VERSION 5.7 ;
  NOWIREEXTENSIONATPIN ON ;
  DIVIDERCHAR "/" ;
  BUSBITCHARS "[]" ;
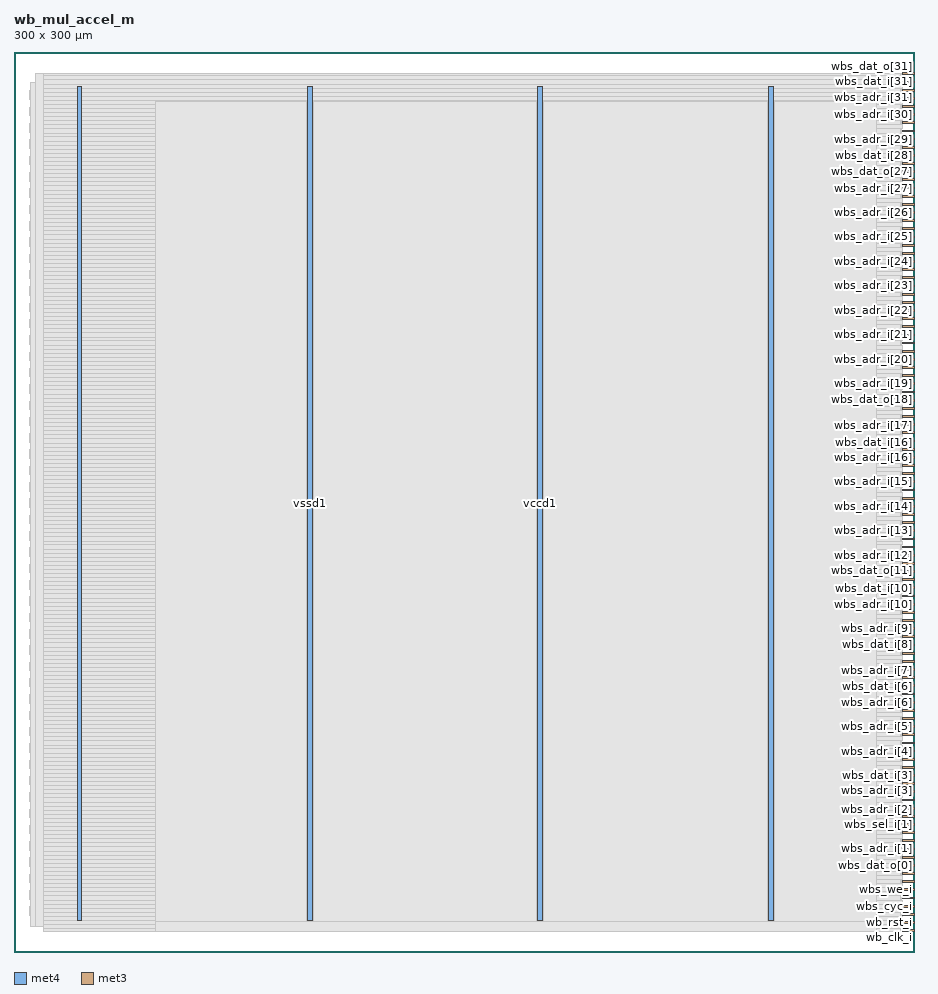
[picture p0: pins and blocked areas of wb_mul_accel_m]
MACRO wb_mul_accel_m
  CLASS BLOCK ;
  FOREIGN wb_mul_accel_m ;
  ORIGIN 0.000 0.000 ;
  SIZE 300.000 BY 300.000 ;
  PIN vccd1
    DIRECTION INOUT ;
    USE POWER ;
    PORT
      LAYER met4 ;
        RECT 21.040 10.640 22.640 288.560 ;
    END
    PORT
      LAYER met4 ;
        RECT 174.640 10.640 176.240 288.560 ;
    END
  END vccd1
  PIN vssd1
    DIRECTION INOUT ;
    USE GROUND ;
    PORT
      LAYER met4 ;
        RECT 97.840 10.640 99.440 288.560 ;
    END
    PORT
      LAYER met4 ;
        RECT 251.440 10.640 253.040 288.560 ;
    END
  END vssd1
  PIN wb_clk_i
    DIRECTION INPUT ;
    USE SIGNAL ;
    ANTENNAGATEAREA 0.852000 ;
    PORT
      LAYER met3 ;
        RECT 296.000 6.840 300.000 7.440 ;
    END
  END wb_clk_i
  PIN wb_rst_i
    DIRECTION INPUT ;
    USE SIGNAL ;
    ANTENNAGATEAREA 0.213000 ;
    PORT
      LAYER met3 ;
        RECT 296.000 9.560 300.000 10.160 ;
    END
  END wb_rst_i
  PIN wbs_ack_o
    DIRECTION OUTPUT TRISTATE ;
    USE SIGNAL ;
    ANTENNADIFFAREA 0.795200 ;
    PORT
      LAYER met3 ;
        RECT 296.000 12.280 300.000 12.880 ;
    END
  END wbs_ack_o
  PIN wbs_adr_i[0]
    DIRECTION INPUT ;
    USE SIGNAL ;
    PORT
      LAYER met3 ;
        RECT 296.000 23.160 300.000 23.760 ;
    END
  END wbs_adr_i[0]
  PIN wbs_adr_i[10]
    DIRECTION INPUT ;
    USE SIGNAL ;
    PORT
      LAYER met3 ;
        RECT 296.000 115.640 300.000 116.240 ;
    END
  END wbs_adr_i[10]
  PIN wbs_adr_i[11]
    DIRECTION INPUT ;
    USE SIGNAL ;
    PORT
      LAYER met3 ;
        RECT 296.000 123.800 300.000 124.400 ;
    END
  END wbs_adr_i[11]
  PIN wbs_adr_i[12]
    DIRECTION INPUT ;
    USE SIGNAL ;
    PORT
      LAYER met3 ;
        RECT 296.000 131.960 300.000 132.560 ;
    END
  END wbs_adr_i[12]
  PIN wbs_adr_i[13]
    DIRECTION INPUT ;
    USE SIGNAL ;
    PORT
      LAYER met3 ;
        RECT 296.000 140.120 300.000 140.720 ;
    END
  END wbs_adr_i[13]
  PIN wbs_adr_i[14]
    DIRECTION INPUT ;
    USE SIGNAL ;
    PORT
      LAYER met3 ;
        RECT 296.000 148.280 300.000 148.880 ;
    END
  END wbs_adr_i[14]
  PIN wbs_adr_i[15]
    DIRECTION INPUT ;
    USE SIGNAL ;
    PORT
      LAYER met3 ;
        RECT 296.000 156.440 300.000 157.040 ;
    END
  END wbs_adr_i[15]
  PIN wbs_adr_i[16]
    DIRECTION INPUT ;
    USE SIGNAL ;
    PORT
      LAYER met3 ;
        RECT 296.000 164.600 300.000 165.200 ;
    END
  END wbs_adr_i[16]
  PIN wbs_adr_i[17]
    DIRECTION INPUT ;
    USE SIGNAL ;
    PORT
      LAYER met3 ;
        RECT 296.000 172.760 300.000 173.360 ;
    END
  END wbs_adr_i[17]
  PIN wbs_adr_i[18]
    DIRECTION INPUT ;
    USE SIGNAL ;
    PORT
      LAYER met3 ;
        RECT 296.000 180.920 300.000 181.520 ;
    END
  END wbs_adr_i[18]
  PIN wbs_adr_i[19]
    DIRECTION INPUT ;
    USE SIGNAL ;
    PORT
      LAYER met3 ;
        RECT 296.000 189.080 300.000 189.680 ;
    END
  END wbs_adr_i[19]
  PIN wbs_adr_i[1]
    DIRECTION INPUT ;
    USE SIGNAL ;
    PORT
      LAYER met3 ;
        RECT 296.000 34.040 300.000 34.640 ;
    END
  END wbs_adr_i[1]
  PIN wbs_adr_i[20]
    DIRECTION INPUT ;
    USE SIGNAL ;
    PORT
      LAYER met3 ;
        RECT 296.000 197.240 300.000 197.840 ;
    END
  END wbs_adr_i[20]
  PIN wbs_adr_i[21]
    DIRECTION INPUT ;
    USE SIGNAL ;
    PORT
      LAYER met3 ;
        RECT 296.000 205.400 300.000 206.000 ;
    END
  END wbs_adr_i[21]
  PIN wbs_adr_i[22]
    DIRECTION INPUT ;
    USE SIGNAL ;
    PORT
      LAYER met3 ;
        RECT 296.000 213.560 300.000 214.160 ;
    END
  END wbs_adr_i[22]
  PIN wbs_adr_i[23]
    DIRECTION INPUT ;
    USE SIGNAL ;
    PORT
      LAYER met3 ;
        RECT 296.000 221.720 300.000 222.320 ;
    END
  END wbs_adr_i[23]
  PIN wbs_adr_i[24]
    DIRECTION INPUT ;
    USE SIGNAL ;
    PORT
      LAYER met3 ;
        RECT 296.000 229.880 300.000 230.480 ;
    END
  END wbs_adr_i[24]
  PIN wbs_adr_i[25]
    DIRECTION INPUT ;
    USE SIGNAL ;
    PORT
      LAYER met3 ;
        RECT 296.000 238.040 300.000 238.640 ;
    END
  END wbs_adr_i[25]
  PIN wbs_adr_i[26]
    DIRECTION INPUT ;
    USE SIGNAL ;
    PORT
      LAYER met3 ;
        RECT 296.000 246.200 300.000 246.800 ;
    END
  END wbs_adr_i[26]
  PIN wbs_adr_i[27]
    DIRECTION INPUT ;
    USE SIGNAL ;
    PORT
      LAYER met3 ;
        RECT 296.000 254.360 300.000 254.960 ;
    END
  END wbs_adr_i[27]
  PIN wbs_adr_i[28]
    DIRECTION INPUT ;
    USE SIGNAL ;
    PORT
      LAYER met3 ;
        RECT 296.000 262.520 300.000 263.120 ;
    END
  END wbs_adr_i[28]
  PIN wbs_adr_i[29]
    DIRECTION INPUT ;
    USE SIGNAL ;
    PORT
      LAYER met3 ;
        RECT 296.000 270.680 300.000 271.280 ;
    END
  END wbs_adr_i[29]
  PIN wbs_adr_i[2]
    DIRECTION INPUT ;
    USE SIGNAL ;
    ANTENNAGATEAREA 0.213000 ;
    PORT
      LAYER met3 ;
        RECT 296.000 44.920 300.000 45.520 ;
    END
  END wbs_adr_i[2]
  PIN wbs_adr_i[30]
    DIRECTION INPUT ;
    USE SIGNAL ;
    PORT
      LAYER met3 ;
        RECT 296.000 278.840 300.000 279.440 ;
    END
  END wbs_adr_i[30]
  PIN wbs_adr_i[31]
    DIRECTION INPUT ;
    USE SIGNAL ;
    PORT
      LAYER met3 ;
        RECT 296.000 287.000 300.000 287.600 ;
    END
  END wbs_adr_i[31]
  PIN wbs_adr_i[3]
    DIRECTION INPUT ;
    USE SIGNAL ;
    ANTENNAGATEAREA 0.196500 ;
    PORT
      LAYER met3 ;
        RECT 296.000 55.800 300.000 56.400 ;
    END
  END wbs_adr_i[3]
  PIN wbs_adr_i[4]
    DIRECTION INPUT ;
    USE SIGNAL ;
    PORT
      LAYER met3 ;
        RECT 296.000 66.680 300.000 67.280 ;
    END
  END wbs_adr_i[4]
  PIN wbs_adr_i[5]
    DIRECTION INPUT ;
    USE SIGNAL ;
    PORT
      LAYER met3 ;
        RECT 296.000 74.840 300.000 75.440 ;
    END
  END wbs_adr_i[5]
  PIN wbs_adr_i[6]
    DIRECTION INPUT ;
    USE SIGNAL ;
    PORT
      LAYER met3 ;
        RECT 296.000 83.000 300.000 83.600 ;
    END
  END wbs_adr_i[6]
  PIN wbs_adr_i[7]
    DIRECTION INPUT ;
    USE SIGNAL ;
    PORT
      LAYER met3 ;
        RECT 296.000 91.160 300.000 91.760 ;
    END
  END wbs_adr_i[7]
  PIN wbs_adr_i[8]
    DIRECTION INPUT ;
    USE SIGNAL ;
    PORT
      LAYER met3 ;
        RECT 296.000 99.320 300.000 99.920 ;
    END
  END wbs_adr_i[8]
  PIN wbs_adr_i[9]
    DIRECTION INPUT ;
    USE SIGNAL ;
    PORT
      LAYER met3 ;
        RECT 296.000 107.480 300.000 108.080 ;
    END
  END wbs_adr_i[9]
  PIN wbs_cyc_i
    DIRECTION INPUT ;
    USE SIGNAL ;
    ANTENNAGATEAREA 0.196500 ;
    PORT
      LAYER met3 ;
        RECT 296.000 15.000 300.000 15.600 ;
    END
  END wbs_cyc_i
  PIN wbs_dat_i[0]
    DIRECTION INPUT ;
    USE SIGNAL ;
    ANTENNAGATEAREA 0.196500 ;
    PORT
      LAYER met3 ;
        RECT 296.000 25.880 300.000 26.480 ;
    END
  END wbs_dat_i[0]
  PIN wbs_dat_i[10]
    DIRECTION INPUT ;
    USE SIGNAL ;
    ANTENNAGATEAREA 0.196500 ;
    PORT
      LAYER met3 ;
        RECT 296.000 118.360 300.000 118.960 ;
    END
  END wbs_dat_i[10]
  PIN wbs_dat_i[11]
    DIRECTION INPUT ;
    USE SIGNAL ;
    ANTENNAGATEAREA 0.196500 ;
    PORT
      LAYER met3 ;
        RECT 296.000 126.520 300.000 127.120 ;
    END
  END wbs_dat_i[11]
  PIN wbs_dat_i[12]
    DIRECTION INPUT ;
    USE SIGNAL ;
    ANTENNAGATEAREA 0.196500 ;
    PORT
      LAYER met3 ;
        RECT 296.000 134.680 300.000 135.280 ;
    END
  END wbs_dat_i[12]
  PIN wbs_dat_i[13]
    DIRECTION INPUT ;
    USE SIGNAL ;
    ANTENNAGATEAREA 0.196500 ;
    PORT
      LAYER met3 ;
        RECT 296.000 142.840 300.000 143.440 ;
    END
  END wbs_dat_i[13]
  PIN wbs_dat_i[14]
    DIRECTION INPUT ;
    USE SIGNAL ;
    ANTENNAGATEAREA 0.196500 ;
    PORT
      LAYER met3 ;
        RECT 296.000 151.000 300.000 151.600 ;
    END
  END wbs_dat_i[14]
  PIN wbs_dat_i[15]
    DIRECTION INPUT ;
    USE SIGNAL ;
    ANTENNAGATEAREA 0.196500 ;
    PORT
      LAYER met3 ;
        RECT 296.000 159.160 300.000 159.760 ;
    END
  END wbs_dat_i[15]
  PIN wbs_dat_i[16]
    DIRECTION INPUT ;
    USE SIGNAL ;
    ANTENNAGATEAREA 0.196500 ;
    PORT
      LAYER met3 ;
        RECT 296.000 167.320 300.000 167.920 ;
    END
  END wbs_dat_i[16]
  PIN wbs_dat_i[17]
    DIRECTION INPUT ;
    USE SIGNAL ;
    ANTENNAGATEAREA 0.196500 ;
    PORT
      LAYER met3 ;
        RECT 296.000 175.480 300.000 176.080 ;
    END
  END wbs_dat_i[17]
  PIN wbs_dat_i[18]
    DIRECTION INPUT ;
    USE SIGNAL ;
    ANTENNAGATEAREA 0.196500 ;
    PORT
      LAYER met3 ;
        RECT 296.000 183.640 300.000 184.240 ;
    END
  END wbs_dat_i[18]
  PIN wbs_dat_i[19]
    DIRECTION INPUT ;
    USE SIGNAL ;
    ANTENNAGATEAREA 0.196500 ;
    PORT
      LAYER met3 ;
        RECT 296.000 191.800 300.000 192.400 ;
    END
  END wbs_dat_i[19]
  PIN wbs_dat_i[1]
    DIRECTION INPUT ;
    USE SIGNAL ;
    ANTENNAGATEAREA 0.196500 ;
    PORT
      LAYER met3 ;
        RECT 296.000 36.760 300.000 37.360 ;
    END
  END wbs_dat_i[1]
  PIN wbs_dat_i[20]
    DIRECTION INPUT ;
    USE SIGNAL ;
    ANTENNAGATEAREA 0.196500 ;
    PORT
      LAYER met3 ;
        RECT 296.000 199.960 300.000 200.560 ;
    END
  END wbs_dat_i[20]
  PIN wbs_dat_i[21]
    DIRECTION INPUT ;
    USE SIGNAL ;
    ANTENNAGATEAREA 0.196500 ;
    PORT
      LAYER met3 ;
        RECT 296.000 208.120 300.000 208.720 ;
    END
  END wbs_dat_i[21]
  PIN wbs_dat_i[22]
    DIRECTION INPUT ;
    USE SIGNAL ;
    ANTENNAGATEAREA 0.196500 ;
    PORT
      LAYER met3 ;
        RECT 296.000 216.280 300.000 216.880 ;
    END
  END wbs_dat_i[22]
  PIN wbs_dat_i[23]
    DIRECTION INPUT ;
    USE SIGNAL ;
    ANTENNAGATEAREA 0.196500 ;
    PORT
      LAYER met3 ;
        RECT 296.000 224.440 300.000 225.040 ;
    END
  END wbs_dat_i[23]
  PIN wbs_dat_i[24]
    DIRECTION INPUT ;
    USE SIGNAL ;
    ANTENNAGATEAREA 0.196500 ;
    PORT
      LAYER met3 ;
        RECT 296.000 232.600 300.000 233.200 ;
    END
  END wbs_dat_i[24]
  PIN wbs_dat_i[25]
    DIRECTION INPUT ;
    USE SIGNAL ;
    ANTENNAGATEAREA 0.196500 ;
    PORT
      LAYER met3 ;
        RECT 296.000 240.760 300.000 241.360 ;
    END
  END wbs_dat_i[25]
  PIN wbs_dat_i[26]
    DIRECTION INPUT ;
    USE SIGNAL ;
    ANTENNAGATEAREA 0.196500 ;
    PORT
      LAYER met3 ;
        RECT 296.000 248.920 300.000 249.520 ;
    END
  END wbs_dat_i[26]
  PIN wbs_dat_i[27]
    DIRECTION INPUT ;
    USE SIGNAL ;
    ANTENNAGATEAREA 0.196500 ;
    PORT
      LAYER met3 ;
        RECT 296.000 257.080 300.000 257.680 ;
    END
  END wbs_dat_i[27]
  PIN wbs_dat_i[28]
    DIRECTION INPUT ;
    USE SIGNAL ;
    ANTENNAGATEAREA 0.196500 ;
    PORT
      LAYER met3 ;
        RECT 296.000 265.240 300.000 265.840 ;
    END
  END wbs_dat_i[28]
  PIN wbs_dat_i[29]
    DIRECTION INPUT ;
    USE SIGNAL ;
    ANTENNAGATEAREA 0.196500 ;
    PORT
      LAYER met3 ;
        RECT 296.000 273.400 300.000 274.000 ;
    END
  END wbs_dat_i[29]
  PIN wbs_dat_i[2]
    DIRECTION INPUT ;
    USE SIGNAL ;
    ANTENNAGATEAREA 0.196500 ;
    PORT
      LAYER met3 ;
        RECT 296.000 47.640 300.000 48.240 ;
    END
  END wbs_dat_i[2]
  PIN wbs_dat_i[30]
    DIRECTION INPUT ;
    USE SIGNAL ;
    ANTENNAGATEAREA 0.196500 ;
    PORT
      LAYER met3 ;
        RECT 296.000 281.560 300.000 282.160 ;
    END
  END wbs_dat_i[30]
  PIN wbs_dat_i[31]
    DIRECTION INPUT ;
    USE SIGNAL ;
    ANTENNAGATEAREA 0.196500 ;
    PORT
      LAYER met3 ;
        RECT 296.000 289.720 300.000 290.320 ;
    END
  END wbs_dat_i[31]
  PIN wbs_dat_i[3]
    DIRECTION INPUT ;
    USE SIGNAL ;
    ANTENNAGATEAREA 0.196500 ;
    PORT
      LAYER met3 ;
        RECT 296.000 58.520 300.000 59.120 ;
    END
  END wbs_dat_i[3]
  PIN wbs_dat_i[4]
    DIRECTION INPUT ;
    USE SIGNAL ;
    ANTENNAGATEAREA 0.196500 ;
    PORT
      LAYER met3 ;
        RECT 296.000 69.400 300.000 70.000 ;
    END
  END wbs_dat_i[4]
  PIN wbs_dat_i[5]
    DIRECTION INPUT ;
    USE SIGNAL ;
    ANTENNAGATEAREA 0.196500 ;
    PORT
      LAYER met3 ;
        RECT 296.000 77.560 300.000 78.160 ;
    END
  END wbs_dat_i[5]
  PIN wbs_dat_i[6]
    DIRECTION INPUT ;
    USE SIGNAL ;
    ANTENNAGATEAREA 0.196500 ;
    PORT
      LAYER met3 ;
        RECT 296.000 85.720 300.000 86.320 ;
    END
  END wbs_dat_i[6]
  PIN wbs_dat_i[7]
    DIRECTION INPUT ;
    USE SIGNAL ;
    ANTENNAGATEAREA 0.196500 ;
    PORT
      LAYER met3 ;
        RECT 296.000 93.880 300.000 94.480 ;
    END
  END wbs_dat_i[7]
  PIN wbs_dat_i[8]
    DIRECTION INPUT ;
    USE SIGNAL ;
    ANTENNAGATEAREA 0.196500 ;
    PORT
      LAYER met3 ;
        RECT 296.000 102.040 300.000 102.640 ;
    END
  END wbs_dat_i[8]
  PIN wbs_dat_i[9]
    DIRECTION INPUT ;
    USE SIGNAL ;
    ANTENNAGATEAREA 0.196500 ;
    PORT
      LAYER met3 ;
        RECT 296.000 110.200 300.000 110.800 ;
    END
  END wbs_dat_i[9]
  PIN wbs_dat_o[0]
    DIRECTION OUTPUT TRISTATE ;
    USE SIGNAL ;
    ANTENNADIFFAREA 0.795200 ;
    PORT
      LAYER met3 ;
        RECT 296.000 28.600 300.000 29.200 ;
    END
  END wbs_dat_o[0]
  PIN wbs_dat_o[10]
    DIRECTION OUTPUT TRISTATE ;
    USE SIGNAL ;
    ANTENNADIFFAREA 0.795200 ;
    PORT
      LAYER met3 ;
        RECT 296.000 121.080 300.000 121.680 ;
    END
  END wbs_dat_o[10]
  PIN wbs_dat_o[11]
    DIRECTION OUTPUT TRISTATE ;
    USE SIGNAL ;
    ANTENNADIFFAREA 0.795200 ;
    PORT
      LAYER met3 ;
        RECT 296.000 129.240 300.000 129.840 ;
    END
  END wbs_dat_o[11]
  PIN wbs_dat_o[12]
    DIRECTION OUTPUT TRISTATE ;
    USE SIGNAL ;
    ANTENNADIFFAREA 0.795200 ;
    PORT
      LAYER met3 ;
        RECT 296.000 137.400 300.000 138.000 ;
    END
  END wbs_dat_o[12]
  PIN wbs_dat_o[13]
    DIRECTION OUTPUT TRISTATE ;
    USE SIGNAL ;
    ANTENNADIFFAREA 0.445500 ;
    PORT
      LAYER met3 ;
        RECT 296.000 145.560 300.000 146.160 ;
    END
  END wbs_dat_o[13]
  PIN wbs_dat_o[14]
    DIRECTION OUTPUT TRISTATE ;
    USE SIGNAL ;
    ANTENNADIFFAREA 0.795200 ;
    PORT
      LAYER met3 ;
        RECT 296.000 153.720 300.000 154.320 ;
    END
  END wbs_dat_o[14]
  PIN wbs_dat_o[15]
    DIRECTION OUTPUT TRISTATE ;
    USE SIGNAL ;
    ANTENNADIFFAREA 0.795200 ;
    PORT
      LAYER met3 ;
        RECT 296.000 161.880 300.000 162.480 ;
    END
  END wbs_dat_o[15]
  PIN wbs_dat_o[16]
    DIRECTION OUTPUT TRISTATE ;
    USE SIGNAL ;
    ANTENNADIFFAREA 0.795200 ;
    PORT
      LAYER met3 ;
        RECT 296.000 170.040 300.000 170.640 ;
    END
  END wbs_dat_o[16]
  PIN wbs_dat_o[17]
    DIRECTION OUTPUT TRISTATE ;
    USE SIGNAL ;
    ANTENNADIFFAREA 0.445500 ;
    PORT
      LAYER met3 ;
        RECT 296.000 178.200 300.000 178.800 ;
    END
  END wbs_dat_o[17]
  PIN wbs_dat_o[18]
    DIRECTION OUTPUT TRISTATE ;
    USE SIGNAL ;
    ANTENNADIFFAREA 0.795200 ;
    PORT
      LAYER met3 ;
        RECT 296.000 186.360 300.000 186.960 ;
    END
  END wbs_dat_o[18]
  PIN wbs_dat_o[19]
    DIRECTION OUTPUT TRISTATE ;
    USE SIGNAL ;
    ANTENNADIFFAREA 0.891000 ;
    PORT
      LAYER met3 ;
        RECT 296.000 194.520 300.000 195.120 ;
    END
  END wbs_dat_o[19]
  PIN wbs_dat_o[1]
    DIRECTION OUTPUT TRISTATE ;
    USE SIGNAL ;
    ANTENNADIFFAREA 0.795200 ;
    PORT
      LAYER met3 ;
        RECT 296.000 39.480 300.000 40.080 ;
    END
  END wbs_dat_o[1]
  PIN wbs_dat_o[20]
    DIRECTION OUTPUT TRISTATE ;
    USE SIGNAL ;
    ANTENNADIFFAREA 0.795200 ;
    PORT
      LAYER met3 ;
        RECT 296.000 202.680 300.000 203.280 ;
    END
  END wbs_dat_o[20]
  PIN wbs_dat_o[21]
    DIRECTION OUTPUT TRISTATE ;
    USE SIGNAL ;
    ANTENNADIFFAREA 0.795200 ;
    PORT
      LAYER met3 ;
        RECT 296.000 210.840 300.000 211.440 ;
    END
  END wbs_dat_o[21]
  PIN wbs_dat_o[22]
    DIRECTION OUTPUT TRISTATE ;
    USE SIGNAL ;
    ANTENNADIFFAREA 0.795200 ;
    PORT
      LAYER met3 ;
        RECT 296.000 219.000 300.000 219.600 ;
    END
  END wbs_dat_o[22]
  PIN wbs_dat_o[23]
    DIRECTION OUTPUT TRISTATE ;
    USE SIGNAL ;
    ANTENNADIFFAREA 0.795200 ;
    PORT
      LAYER met3 ;
        RECT 296.000 227.160 300.000 227.760 ;
    END
  END wbs_dat_o[23]
  PIN wbs_dat_o[24]
    DIRECTION OUTPUT TRISTATE ;
    USE SIGNAL ;
    ANTENNADIFFAREA 0.795200 ;
    PORT
      LAYER met3 ;
        RECT 296.000 235.320 300.000 235.920 ;
    END
  END wbs_dat_o[24]
  PIN wbs_dat_o[25]
    DIRECTION OUTPUT TRISTATE ;
    USE SIGNAL ;
    ANTENNADIFFAREA 0.795200 ;
    PORT
      LAYER met3 ;
        RECT 296.000 243.480 300.000 244.080 ;
    END
  END wbs_dat_o[25]
  PIN wbs_dat_o[26]
    DIRECTION OUTPUT TRISTATE ;
    USE SIGNAL ;
    ANTENNADIFFAREA 0.795200 ;
    PORT
      LAYER met3 ;
        RECT 296.000 251.640 300.000 252.240 ;
    END
  END wbs_dat_o[26]
  PIN wbs_dat_o[27]
    DIRECTION OUTPUT TRISTATE ;
    USE SIGNAL ;
    ANTENNADIFFAREA 0.795200 ;
    PORT
      LAYER met3 ;
        RECT 296.000 259.800 300.000 260.400 ;
    END
  END wbs_dat_o[27]
  PIN wbs_dat_o[28]
    DIRECTION OUTPUT TRISTATE ;
    USE SIGNAL ;
    ANTENNADIFFAREA 0.795200 ;
    PORT
      LAYER met3 ;
        RECT 296.000 267.960 300.000 268.560 ;
    END
  END wbs_dat_o[28]
  PIN wbs_dat_o[29]
    DIRECTION OUTPUT TRISTATE ;
    USE SIGNAL ;
    ANTENNADIFFAREA 0.795200 ;
    PORT
      LAYER met3 ;
        RECT 296.000 276.120 300.000 276.720 ;
    END
  END wbs_dat_o[29]
  PIN wbs_dat_o[2]
    DIRECTION OUTPUT TRISTATE ;
    USE SIGNAL ;
    ANTENNADIFFAREA 0.795200 ;
    PORT
      LAYER met3 ;
        RECT 296.000 50.360 300.000 50.960 ;
    END
  END wbs_dat_o[2]
  PIN wbs_dat_o[30]
    DIRECTION OUTPUT TRISTATE ;
    USE SIGNAL ;
    ANTENNADIFFAREA 1.336500 ;
    PORT
      LAYER met3 ;
        RECT 296.000 284.280 300.000 284.880 ;
    END
  END wbs_dat_o[30]
  PIN wbs_dat_o[31]
    DIRECTION OUTPUT TRISTATE ;
    USE SIGNAL ;
    ANTENNADIFFAREA 1.336500 ;
    PORT
      LAYER met3 ;
        RECT 296.000 292.440 300.000 293.040 ;
    END
  END wbs_dat_o[31]
  PIN wbs_dat_o[3]
    DIRECTION OUTPUT TRISTATE ;
    USE SIGNAL ;
    ANTENNADIFFAREA 0.795200 ;
    PORT
      LAYER met3 ;
        RECT 296.000 61.240 300.000 61.840 ;
    END
  END wbs_dat_o[3]
  PIN wbs_dat_o[4]
    DIRECTION OUTPUT TRISTATE ;
    USE SIGNAL ;
    ANTENNADIFFAREA 0.445500 ;
    PORT
      LAYER met3 ;
        RECT 296.000 72.120 300.000 72.720 ;
    END
  END wbs_dat_o[4]
  PIN wbs_dat_o[5]
    DIRECTION OUTPUT TRISTATE ;
    USE SIGNAL ;
    ANTENNADIFFAREA 0.445500 ;
    PORT
      LAYER met3 ;
        RECT 296.000 80.280 300.000 80.880 ;
    END
  END wbs_dat_o[5]
  PIN wbs_dat_o[6]
    DIRECTION OUTPUT TRISTATE ;
    USE SIGNAL ;
    ANTENNADIFFAREA 0.795200 ;
    PORT
      LAYER met3 ;
        RECT 296.000 88.440 300.000 89.040 ;
    END
  END wbs_dat_o[6]
  PIN wbs_dat_o[7]
    DIRECTION OUTPUT TRISTATE ;
    USE SIGNAL ;
    ANTENNADIFFAREA 0.795200 ;
    PORT
      LAYER met3 ;
        RECT 296.000 96.600 300.000 97.200 ;
    END
  END wbs_dat_o[7]
  PIN wbs_dat_o[8]
    DIRECTION OUTPUT TRISTATE ;
    USE SIGNAL ;
    ANTENNADIFFAREA 0.795200 ;
    PORT
      LAYER met3 ;
        RECT 296.000 104.760 300.000 105.360 ;
    END
  END wbs_dat_o[8]
  PIN wbs_dat_o[9]
    DIRECTION OUTPUT TRISTATE ;
    USE SIGNAL ;
    ANTENNADIFFAREA 0.795200 ;
    PORT
      LAYER met3 ;
        RECT 296.000 112.920 300.000 113.520 ;
    END
  END wbs_dat_o[9]
  PIN wbs_sel_i[0]
    DIRECTION INPUT ;
    USE SIGNAL ;
    PORT
      LAYER met3 ;
        RECT 296.000 31.320 300.000 31.920 ;
    END
  END wbs_sel_i[0]
  PIN wbs_sel_i[1]
    DIRECTION INPUT ;
    USE SIGNAL ;
    PORT
      LAYER met3 ;
        RECT 296.000 42.200 300.000 42.800 ;
    END
  END wbs_sel_i[1]
  PIN wbs_sel_i[2]
    DIRECTION INPUT ;
    USE SIGNAL ;
    PORT
      LAYER met3 ;
        RECT 296.000 53.080 300.000 53.680 ;
    END
  END wbs_sel_i[2]
  PIN wbs_sel_i[3]
    DIRECTION INPUT ;
    USE SIGNAL ;
    PORT
      LAYER met3 ;
        RECT 296.000 63.960 300.000 64.560 ;
    END
  END wbs_sel_i[3]
  PIN wbs_stb_i
    DIRECTION INPUT ;
    USE SIGNAL ;
    ANTENNAGATEAREA 0.196500 ;
    PORT
      LAYER met3 ;
        RECT 296.000 17.720 300.000 18.320 ;
    END
  END wbs_stb_i
  PIN wbs_we_i
    DIRECTION INPUT ;
    USE SIGNAL ;
    ANTENNAGATEAREA 0.196500 ;
    PORT
      LAYER met3 ;
        RECT 296.000 20.440 300.000 21.040 ;
    END
  END wbs_we_i
  OBS
      LAYER nwell ;
        RECT 5.330 284.185 294.590 287.015 ;
        RECT 5.330 278.745 294.590 281.575 ;
        RECT 5.330 273.305 294.590 276.135 ;
        RECT 5.330 267.865 294.590 270.695 ;
        RECT 5.330 262.425 294.590 265.255 ;
        RECT 5.330 256.985 294.590 259.815 ;
        RECT 5.330 251.545 294.590 254.375 ;
        RECT 5.330 246.105 294.590 248.935 ;
        RECT 5.330 240.665 294.590 243.495 ;
        RECT 5.330 235.225 294.590 238.055 ;
        RECT 5.330 229.785 294.590 232.615 ;
        RECT 5.330 224.345 294.590 227.175 ;
        RECT 5.330 218.905 294.590 221.735 ;
        RECT 5.330 213.465 294.590 216.295 ;
        RECT 5.330 208.025 294.590 210.855 ;
        RECT 5.330 202.585 294.590 205.415 ;
        RECT 5.330 197.145 294.590 199.975 ;
        RECT 5.330 191.705 294.590 194.535 ;
        RECT 5.330 186.265 294.590 189.095 ;
        RECT 5.330 180.825 294.590 183.655 ;
        RECT 5.330 175.385 294.590 178.215 ;
        RECT 5.330 169.945 294.590 172.775 ;
        RECT 5.330 164.505 294.590 167.335 ;
        RECT 5.330 159.065 294.590 161.895 ;
        RECT 5.330 153.625 294.590 156.455 ;
        RECT 5.330 148.185 294.590 151.015 ;
        RECT 5.330 142.745 294.590 145.575 ;
        RECT 5.330 137.305 294.590 140.135 ;
        RECT 5.330 131.865 294.590 134.695 ;
        RECT 5.330 126.425 294.590 129.255 ;
        RECT 5.330 120.985 294.590 123.815 ;
        RECT 5.330 115.545 294.590 118.375 ;
        RECT 5.330 110.105 294.590 112.935 ;
        RECT 5.330 104.665 294.590 107.495 ;
        RECT 5.330 99.225 294.590 102.055 ;
        RECT 5.330 93.785 294.590 96.615 ;
        RECT 5.330 88.345 294.590 91.175 ;
        RECT 5.330 82.905 294.590 85.735 ;
        RECT 5.330 77.465 294.590 80.295 ;
        RECT 5.330 72.025 294.590 74.855 ;
        RECT 5.330 66.585 294.590 69.415 ;
        RECT 5.330 61.145 294.590 63.975 ;
        RECT 5.330 55.705 294.590 58.535 ;
        RECT 5.330 50.265 294.590 53.095 ;
        RECT 5.330 44.825 294.590 47.655 ;
        RECT 5.330 39.385 294.590 42.215 ;
        RECT 5.330 33.945 294.590 36.775 ;
        RECT 5.330 28.505 294.590 31.335 ;
        RECT 5.330 23.065 294.590 25.895 ;
        RECT 5.330 17.625 294.590 20.455 ;
        RECT 5.330 12.185 294.590 15.015 ;
      LAYER li1 ;
        RECT 5.520 10.795 294.400 288.405 ;
      LAYER met1 ;
        RECT 5.520 8.540 295.710 289.980 ;
      LAYER met2 ;
        RECT 7.000 8.510 295.680 292.925 ;
      LAYER met3 ;
        RECT 9.725 292.040 295.600 292.905 ;
        RECT 9.725 290.720 296.000 292.040 ;
        RECT 9.725 289.320 295.600 290.720 ;
        RECT 9.725 288.000 296.000 289.320 ;
        RECT 9.725 286.600 295.600 288.000 ;
        RECT 9.725 285.280 296.000 286.600 ;
        RECT 9.725 283.880 295.600 285.280 ;
        RECT 9.725 282.560 296.000 283.880 ;
        RECT 9.725 281.160 295.600 282.560 ;
        RECT 9.725 279.840 296.000 281.160 ;
        RECT 9.725 278.440 295.600 279.840 ;
        RECT 9.725 277.120 296.000 278.440 ;
        RECT 9.725 275.720 295.600 277.120 ;
        RECT 9.725 274.400 296.000 275.720 ;
        RECT 9.725 273.000 295.600 274.400 ;
        RECT 9.725 271.680 296.000 273.000 ;
        RECT 9.725 270.280 295.600 271.680 ;
        RECT 9.725 268.960 296.000 270.280 ;
        RECT 9.725 267.560 295.600 268.960 ;
        RECT 9.725 266.240 296.000 267.560 ;
        RECT 9.725 264.840 295.600 266.240 ;
        RECT 9.725 263.520 296.000 264.840 ;
        RECT 9.725 262.120 295.600 263.520 ;
        RECT 9.725 260.800 296.000 262.120 ;
        RECT 9.725 259.400 295.600 260.800 ;
        RECT 9.725 258.080 296.000 259.400 ;
        RECT 9.725 256.680 295.600 258.080 ;
        RECT 9.725 255.360 296.000 256.680 ;
        RECT 9.725 253.960 295.600 255.360 ;
        RECT 9.725 252.640 296.000 253.960 ;
        RECT 9.725 251.240 295.600 252.640 ;
        RECT 9.725 249.920 296.000 251.240 ;
        RECT 9.725 248.520 295.600 249.920 ;
        RECT 9.725 247.200 296.000 248.520 ;
        RECT 9.725 245.800 295.600 247.200 ;
        RECT 9.725 244.480 296.000 245.800 ;
        RECT 9.725 243.080 295.600 244.480 ;
        RECT 9.725 241.760 296.000 243.080 ;
        RECT 9.725 240.360 295.600 241.760 ;
        RECT 9.725 239.040 296.000 240.360 ;
        RECT 9.725 237.640 295.600 239.040 ;
        RECT 9.725 236.320 296.000 237.640 ;
        RECT 9.725 234.920 295.600 236.320 ;
        RECT 9.725 233.600 296.000 234.920 ;
        RECT 9.725 232.200 295.600 233.600 ;
        RECT 9.725 230.880 296.000 232.200 ;
        RECT 9.725 229.480 295.600 230.880 ;
        RECT 9.725 228.160 296.000 229.480 ;
        RECT 9.725 226.760 295.600 228.160 ;
        RECT 9.725 225.440 296.000 226.760 ;
        RECT 9.725 224.040 295.600 225.440 ;
        RECT 9.725 222.720 296.000 224.040 ;
        RECT 9.725 221.320 295.600 222.720 ;
        RECT 9.725 220.000 296.000 221.320 ;
        RECT 9.725 218.600 295.600 220.000 ;
        RECT 9.725 217.280 296.000 218.600 ;
        RECT 9.725 215.880 295.600 217.280 ;
        RECT 9.725 214.560 296.000 215.880 ;
        RECT 9.725 213.160 295.600 214.560 ;
        RECT 9.725 211.840 296.000 213.160 ;
        RECT 9.725 210.440 295.600 211.840 ;
        RECT 9.725 209.120 296.000 210.440 ;
        RECT 9.725 207.720 295.600 209.120 ;
        RECT 9.725 206.400 296.000 207.720 ;
        RECT 9.725 205.000 295.600 206.400 ;
        RECT 9.725 203.680 296.000 205.000 ;
        RECT 9.725 202.280 295.600 203.680 ;
        RECT 9.725 200.960 296.000 202.280 ;
        RECT 9.725 199.560 295.600 200.960 ;
        RECT 9.725 198.240 296.000 199.560 ;
        RECT 9.725 196.840 295.600 198.240 ;
        RECT 9.725 195.520 296.000 196.840 ;
        RECT 9.725 194.120 295.600 195.520 ;
        RECT 9.725 192.800 296.000 194.120 ;
        RECT 9.725 191.400 295.600 192.800 ;
        RECT 9.725 190.080 296.000 191.400 ;
        RECT 9.725 188.680 295.600 190.080 ;
        RECT 9.725 187.360 296.000 188.680 ;
        RECT 9.725 185.960 295.600 187.360 ;
        RECT 9.725 184.640 296.000 185.960 ;
        RECT 9.725 183.240 295.600 184.640 ;
        RECT 9.725 181.920 296.000 183.240 ;
        RECT 9.725 180.520 295.600 181.920 ;
        RECT 9.725 179.200 296.000 180.520 ;
        RECT 9.725 177.800 295.600 179.200 ;
        RECT 9.725 176.480 296.000 177.800 ;
        RECT 9.725 175.080 295.600 176.480 ;
        RECT 9.725 173.760 296.000 175.080 ;
        RECT 9.725 172.360 295.600 173.760 ;
        RECT 9.725 171.040 296.000 172.360 ;
        RECT 9.725 169.640 295.600 171.040 ;
        RECT 9.725 168.320 296.000 169.640 ;
        RECT 9.725 166.920 295.600 168.320 ;
        RECT 9.725 165.600 296.000 166.920 ;
        RECT 9.725 164.200 295.600 165.600 ;
        RECT 9.725 162.880 296.000 164.200 ;
        RECT 9.725 161.480 295.600 162.880 ;
        RECT 9.725 160.160 296.000 161.480 ;
        RECT 9.725 158.760 295.600 160.160 ;
        RECT 9.725 157.440 296.000 158.760 ;
        RECT 9.725 156.040 295.600 157.440 ;
        RECT 9.725 154.720 296.000 156.040 ;
        RECT 9.725 153.320 295.600 154.720 ;
        RECT 9.725 152.000 296.000 153.320 ;
        RECT 9.725 150.600 295.600 152.000 ;
        RECT 9.725 149.280 296.000 150.600 ;
        RECT 9.725 147.880 295.600 149.280 ;
        RECT 9.725 146.560 296.000 147.880 ;
        RECT 9.725 145.160 295.600 146.560 ;
        RECT 9.725 143.840 296.000 145.160 ;
        RECT 9.725 142.440 295.600 143.840 ;
        RECT 9.725 141.120 296.000 142.440 ;
        RECT 9.725 139.720 295.600 141.120 ;
        RECT 9.725 138.400 296.000 139.720 ;
        RECT 9.725 137.000 295.600 138.400 ;
        RECT 9.725 135.680 296.000 137.000 ;
        RECT 9.725 134.280 295.600 135.680 ;
        RECT 9.725 132.960 296.000 134.280 ;
        RECT 9.725 131.560 295.600 132.960 ;
        RECT 9.725 130.240 296.000 131.560 ;
        RECT 9.725 128.840 295.600 130.240 ;
        RECT 9.725 127.520 296.000 128.840 ;
        RECT 9.725 126.120 295.600 127.520 ;
        RECT 9.725 124.800 296.000 126.120 ;
        RECT 9.725 123.400 295.600 124.800 ;
        RECT 9.725 122.080 296.000 123.400 ;
        RECT 9.725 120.680 295.600 122.080 ;
        RECT 9.725 119.360 296.000 120.680 ;
        RECT 9.725 117.960 295.600 119.360 ;
        RECT 9.725 116.640 296.000 117.960 ;
        RECT 9.725 115.240 295.600 116.640 ;
        RECT 9.725 113.920 296.000 115.240 ;
        RECT 9.725 112.520 295.600 113.920 ;
        RECT 9.725 111.200 296.000 112.520 ;
        RECT 9.725 109.800 295.600 111.200 ;
        RECT 9.725 108.480 296.000 109.800 ;
        RECT 9.725 107.080 295.600 108.480 ;
        RECT 9.725 105.760 296.000 107.080 ;
        RECT 9.725 104.360 295.600 105.760 ;
        RECT 9.725 103.040 296.000 104.360 ;
        RECT 9.725 101.640 295.600 103.040 ;
        RECT 9.725 100.320 296.000 101.640 ;
        RECT 9.725 98.920 295.600 100.320 ;
        RECT 9.725 97.600 296.000 98.920 ;
        RECT 9.725 96.200 295.600 97.600 ;
        RECT 9.725 94.880 296.000 96.200 ;
        RECT 9.725 93.480 295.600 94.880 ;
        RECT 9.725 92.160 296.000 93.480 ;
        RECT 9.725 90.760 295.600 92.160 ;
        RECT 9.725 89.440 296.000 90.760 ;
        RECT 9.725 88.040 295.600 89.440 ;
        RECT 9.725 86.720 296.000 88.040 ;
        RECT 9.725 85.320 295.600 86.720 ;
        RECT 9.725 84.000 296.000 85.320 ;
        RECT 9.725 82.600 295.600 84.000 ;
        RECT 9.725 81.280 296.000 82.600 ;
        RECT 9.725 79.880 295.600 81.280 ;
        RECT 9.725 78.560 296.000 79.880 ;
        RECT 9.725 77.160 295.600 78.560 ;
        RECT 9.725 75.840 296.000 77.160 ;
        RECT 9.725 74.440 295.600 75.840 ;
        RECT 9.725 73.120 296.000 74.440 ;
        RECT 9.725 71.720 295.600 73.120 ;
        RECT 9.725 70.400 296.000 71.720 ;
        RECT 9.725 69.000 295.600 70.400 ;
        RECT 9.725 67.680 296.000 69.000 ;
        RECT 9.725 66.280 295.600 67.680 ;
        RECT 9.725 64.960 296.000 66.280 ;
        RECT 9.725 63.560 295.600 64.960 ;
        RECT 9.725 62.240 296.000 63.560 ;
        RECT 9.725 60.840 295.600 62.240 ;
        RECT 9.725 59.520 296.000 60.840 ;
        RECT 9.725 58.120 295.600 59.520 ;
        RECT 9.725 56.800 296.000 58.120 ;
        RECT 9.725 55.400 295.600 56.800 ;
        RECT 9.725 54.080 296.000 55.400 ;
        RECT 9.725 52.680 295.600 54.080 ;
        RECT 9.725 51.360 296.000 52.680 ;
        RECT 9.725 49.960 295.600 51.360 ;
        RECT 9.725 48.640 296.000 49.960 ;
        RECT 9.725 47.240 295.600 48.640 ;
        RECT 9.725 45.920 296.000 47.240 ;
        RECT 9.725 44.520 295.600 45.920 ;
        RECT 9.725 43.200 296.000 44.520 ;
        RECT 9.725 41.800 295.600 43.200 ;
        RECT 9.725 40.480 296.000 41.800 ;
        RECT 9.725 39.080 295.600 40.480 ;
        RECT 9.725 37.760 296.000 39.080 ;
        RECT 9.725 36.360 295.600 37.760 ;
        RECT 9.725 35.040 296.000 36.360 ;
        RECT 9.725 33.640 295.600 35.040 ;
        RECT 9.725 32.320 296.000 33.640 ;
        RECT 9.725 30.920 295.600 32.320 ;
        RECT 9.725 29.600 296.000 30.920 ;
        RECT 9.725 28.200 295.600 29.600 ;
        RECT 9.725 26.880 296.000 28.200 ;
        RECT 9.725 25.480 295.600 26.880 ;
        RECT 9.725 24.160 296.000 25.480 ;
        RECT 9.725 22.760 295.600 24.160 ;
        RECT 9.725 21.440 296.000 22.760 ;
        RECT 9.725 20.040 295.600 21.440 ;
        RECT 9.725 18.720 296.000 20.040 ;
        RECT 9.725 17.320 295.600 18.720 ;
        RECT 9.725 16.000 296.000 17.320 ;
        RECT 9.725 14.600 295.600 16.000 ;
        RECT 9.725 13.280 296.000 14.600 ;
        RECT 9.725 11.880 295.600 13.280 ;
        RECT 9.725 10.560 296.000 11.880 ;
        RECT 9.725 9.160 295.600 10.560 ;
        RECT 9.725 7.840 296.000 9.160 ;
        RECT 9.725 6.980 295.600 7.840 ;
      LAYER met4 ;
        RECT 47.215 10.240 97.440 283.385 ;
        RECT 99.840 10.240 174.240 283.385 ;
        RECT 176.640 10.240 251.040 283.385 ;
        RECT 253.440 10.240 287.665 283.385 ;
        RECT 47.215 6.975 287.665 10.240 ;
  END
END wb_mul_accel_m
END LIBRARY

